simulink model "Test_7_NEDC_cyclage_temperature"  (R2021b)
settings: Solver=FixedStepAuto  StartTime=0.0  StopTime=60*60*3.5
undefined symbols (not defined in the file): Ion, Lithium, Pe
libraries: fl_lib x31, nesl_utility x24, sdl_lib x11, simulink x5, simulink_extras x2, spsBatteryLib x1, spsCurrentVoltageSimscapeInterfaceLib x1, slpidlib x1, spspowerguiLib x1
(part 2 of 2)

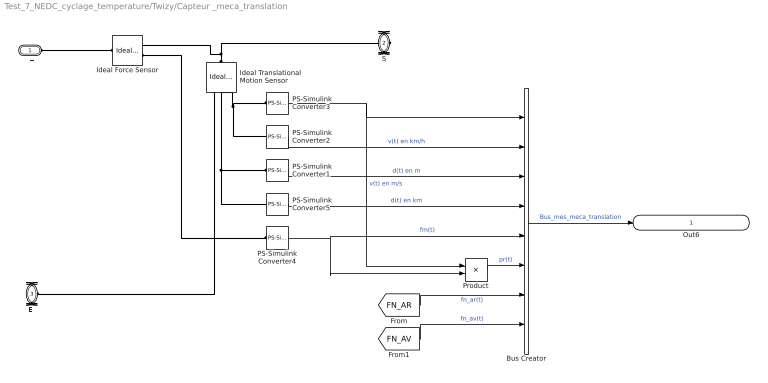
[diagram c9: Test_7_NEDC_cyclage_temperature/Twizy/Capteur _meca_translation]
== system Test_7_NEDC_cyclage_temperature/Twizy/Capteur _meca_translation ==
  Bus Creator : BusCreator  Inputs=8
  Ideal Force Sensor : fl_lib/Mechanical/Mechanical Sensors/Ideal Force Sensor
  Ideal Translational Motion Sensor : fl_lib/Mechanical/Mechanical Sensors/Ideal Translational Motion Sensor  offset=0 m
  PS-Simulink Converter1 : nesl_utility/PS-Simulink Converter  PhysicalDomain=network_engine_domain  SubClassName=ps_output  LeftPortType=input  RightPortType=output  PseudoPeriodic=off  Frequencies=[]  Unit=m  AffineConversion=off
  PS-Simulink Converter2 : nesl_utility/PS-Simulink Converter  PhysicalDomain=network_engine_domain  SubClassName=ps_output  LeftPortType=input  RightPortType=output  PseudoPeriodic=off  Frequencies=[]  Unit=km/hr  AffineConversion=off
  PS-Simulink Converter3 : nesl_utility/PS-Simulink Converter  PhysicalDomain=network_engine_domain  SubClassName=ps_output  LeftPortType=input  RightPortType=output  PseudoPeriodic=off  Frequencies=[]  Unit=m/s  AffineConversion=off
  PS-Simulink Converter4 : nesl_utility/PS-Simulink Converter  PhysicalDomain=network_engine_domain  SubClassName=ps_output  LeftPortType=input  RightPortType=output  PseudoPeriodic=off  Frequencies=[]  Unit=N  AffineConversion=off
  PS-Simulink Converter5 : nesl_utility/PS-Simulink Converter  PhysicalDomain=network_engine_domain  SubClassName=ps_output  LeftPortType=input  RightPortType=output  PseudoPeriodic=off  Frequencies=[]  Unit=km  AffineConversion=off
  Product : Product
  E+ : PMIOPort  Side=Left
  S : PMIOPort  Port=2  Side=Right
  E- : PMIOPort  Port=3  Side=Left
  Out6 : Outport  VectorParamsAs1DForOutWhenUnconnected=off
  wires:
  PS-Simulink Converter3/1 -> Product/1, Bus Creator/1  "v(t) en m/s"
  PS-Simulink Converter4/1 -> Bus Creator/5, Product/2  "fm(t)"
  Product/1 -> Bus Creator/6  "pr(t)"
  Bus Creator/1 -> Out6/1  "Bus_mes_meca_translation"
  PS-Simulink Converter1/1 -> Bus Creator/3  "d(t) en m"
  [FN_AR] -> Bus Creator/7  "fn_ar(t)"
  [FN_AV] -> Bus Creator/8  "fn_av(t)"
  PS-Simulink Converter2/1 -> Bus Creator/2  "v(t) en km/h"
  PS-Simulink Converter5/1 -> Bus Creator/4  "d(t) en km"
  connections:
  PS-Simulink Converter4/LConn1 -- Ideal Force Sensor/RConn2
  Ideal Translational Motion Sensor/LConn1 -- Ideal Force Sensor/RConn1 -- S/RConn1
  PS-Simulink Converter3/LConn1 -- PS-Simulink Converter2/LConn1 -- Ideal Translational Motion Sensor/RConn2
  Ideal Force Sensor/LConn1 -- E+/RConn1
  Ideal Translational Motion Sensor/RConn1 -- E-/RConn1
  PS-Simulink Converter1/LConn1 -- Ideal Translational Motion Sensor/RConn3 -- PS-Simulink Converter5/LConn1

== matlab function Test_7_NEDC_cyclage_temperature/Modele ensemble variateur Sevcon et moteur asynchrone Letrika
en fonctionnement moyen/MATLAB Function1 ==
function I_bat = fcn(Pmeca,rend_var,rend_mot,U_bat)
if Pmeca < 0
    P_elec = Pmeca*(rend_mot/100)*(rend_var/100);    
elseif Pmeca > 0
    P_elec = Pmeca/((rend_mot/100)*(rend_var/100)); 
else
    P_elec = 0;   
end
I_bat = P_elec/U_bat;
end

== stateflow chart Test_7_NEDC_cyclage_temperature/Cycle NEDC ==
  state Cycles_NDEC
    during:
    Consigne_acc=10*Consigne/8;
    state E0
      entry:
      Nb_cycle = Nb_cycle + 1;
      Consigne=0;
    state E01
      during:
      t=temporalCount(sec);
      Consigne=25*t/13;
    state E016
      Consigne=70;
    state E02
      Consigne=15;
    state E017
      during:
      t=temporalCount(sec);
      Consigne=70-25*t/13;
    state E03
      during:
      t=temporalCount(sec);
      Consigne=15-25*t/13;
    state E05
      during:
      t=temporalCount(sec);
      Consigne=25*t/13;
    state E018
      Consigne=50;
    state E04
      Consigne=0;
    state E06
      Consigne=32;
    state E019
      during:
      t=temporalCount(sec);
      Consigne=50+25*t/13;
    state E07
      during:
      t=temporalCount(sec);
      Consigne=32-25*t/13;
    state E020
      Consigne=70;
    state E08
      Consigne=0;
    state E011
      during:
      t=temporalCount(sec);
      Consigne=25*t/13;
    state E021
      during:
      t=temporalCount(sec);
      Consigne=70+25*t/13;
    state E025
      during:
      t=temporalCount(sec);
      Consigne=130-25*t/13;
    state E012
      Consigne=50;
    state E022
      Consigne=100;
    state E09
      during:
      t=temporalCount(sec);
      Consigne=50-25*t/13;
    state E023
      during:
      t=temporalCount(sec);
      Consigne=100+25*t/13;
    state E024
      Consigne=130;
    state E010
      Consigne=35;
    state E015
      during:
      t=temporalCount(sec);
      Consigne=35-25*t/13;
    Cycles_NDEC -> E0 : [Stop==1]
    (default) -> E0 : {Nb_cycle=0;}
    E025 -> E0 : [Consigne<=0]{Nb_cycle=0;}
    E0 -> E01 : after(8,sec)
    E015 -> E0 : [Consigne<=0]
    E01 -> E016 : [Consigne>=70&&Nb_cycle>4]
    E01 -> E02 : [Consigne>=15&&Nb_cycle<=4]
    E016 -> E017 : after(60,sec)
    E02 -> E03 : after(8,sec)
    E017 -> E018 : [Consigne<=50]
    E03 -> E04 : [Consigne<=0]
    E04 -> E05 : after(20,sec)
    E018 -> E019 : after(75,sec)
    E05 -> E06 : [Consigne>=32]
    E06 -> E07 : after(20,sec)
    E019 -> E020 : [Consigne>=70]
    E07 -> E08 : [Consigne<=0]
    E020 -> E021 : after(54,sec)
    E08 -> E011 : after(20,sec)
    E011 -> E012 : [Consigne>=50]
    E021 -> E022 : [Consigne>=100]
    E012 -> E09 : after(8,sec)
    E024 -> E025 : after(10,sec)
    E022 -> E023 : after(40,sec)
    E023 -> E024 : [Consigne>=130]
    E09 -> E010 : [Consigne<=35]
    E010 -> E015 : after(8,sec)
  (default) -> Cycles_NDEC
  data: Consigne output; t local; Nb_cycle local; Consigne_acc output; Stop input

== matlab function Test_7_NEDC_cyclage_temperature/Modele ensemble variateur Sevcon et moteur asynchrone Letrika
en fonctionnement moyen/Capteur meca rotation/MATLAB Function2 ==
function Quadrant_meca = fcn(Cm,Nm)
if Nm > 1
    if Cm > 0
        Quadrant_meca = 1;
    elseif Cm < 0
        Quadrant_meca = 4;
    else
        Quadrant_meca = 0;
    end
elseif Nm < -1
    if Cm > 0
        Quadrant_meca = 2;
    elseif Cm < 0
        Quadrant_meca = 3;
    else
        Quadrant_meca = 0;
    end
else
    Quadrant_meca = 0;
end
end

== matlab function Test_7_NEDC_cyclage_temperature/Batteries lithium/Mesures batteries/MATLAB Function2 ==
function Quadrant_elec = fcn(I_bat,U_bat)
if U_bat > 0.8
    if I_bat > 0.3
        Quadrant_elec = 1;
    elseif I_bat < -0.5
        Quadrant_elec = 4;
    else
        Quadrant_elec = 0;
    end
elseif U_bat < -0.8
    if I_bat > 0.5
        Quadrant_elec = 2;
    elseif I_bat < -0.5
        Quadrant_elec = 3;
    else
        Quadrant_elec = 0;
    end
else
    Quadrant_elec = 0;
end
end

== matlab function Test_7_NEDC_cyclage_temperature/Modele ensemble variateur Sevcon et moteur asynchrone Letrika
en fonctionnement moyen/MATLAB Function ==
function [T_out,P_meca]= fcn(Consigne_frequence, T_in,Nn,Tn,Un,U_bat,Nmes)
if U_bat <= Un
    k_corr = (U_bat/Un).^2;
else
    k_corr = 1;
end
P_max = Tn*(2*pi*Nn/60)*k_corr;

if Consigne_frequence~=0
    if abs(Nmes)<=Nn
        if abs(T_in)>=Tn*k_corr
            T_out=Tn*sign(T_in)*k_corr;
        else
            T_out=T_in*k_corr;
        end
    else
        if abs(T_in)>=P_max/(2*pi*Nmes/60)
            T_out=sign(T_in)*P_max/(2*pi*Nmes/60);
        else
            T_out=T_in;
        end
    end
else
    T_out=0;
end

P_meca = T_out*2*pi*Nmes/60;

end
